VERSION 5.7 ;
  NOWIREEXTENSIONATPIN ON ;
  DIVIDERCHAR "/" ;
  BUSBITCHARS "[]" ;
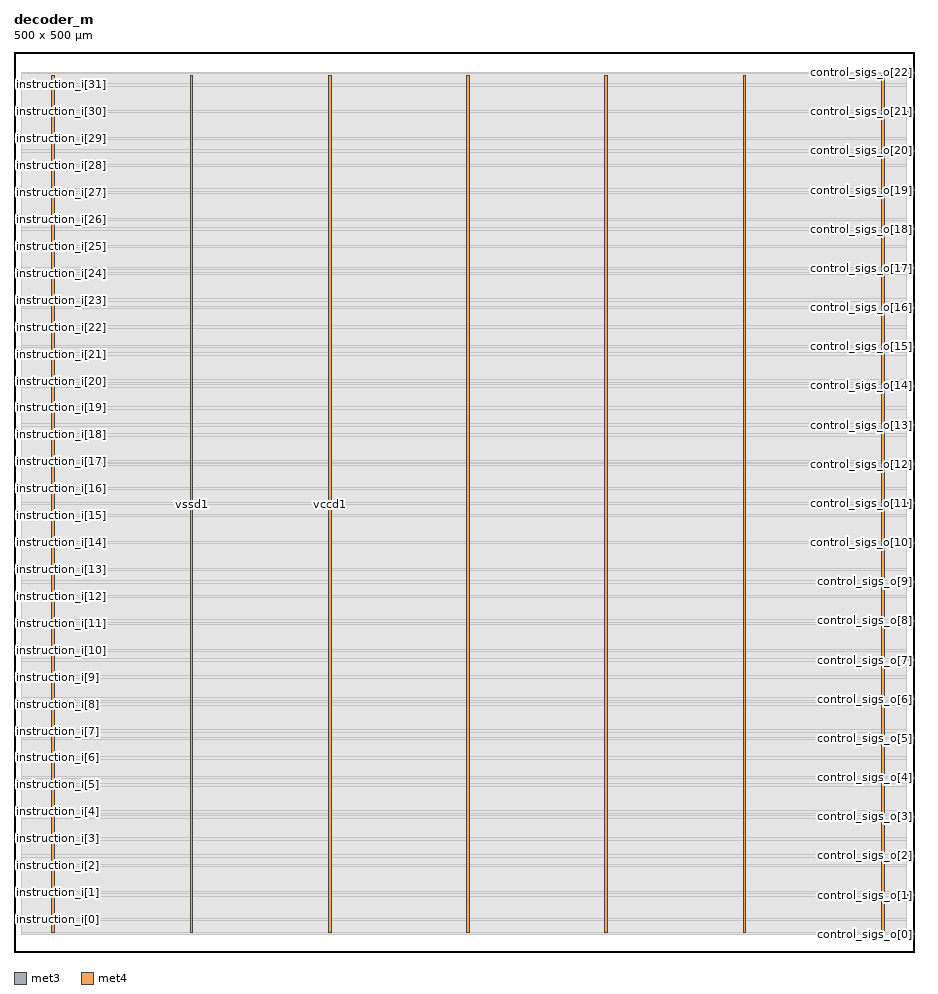
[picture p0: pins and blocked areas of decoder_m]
MACRO decoder_m
  CLASS BLOCK ;
  FOREIGN decoder_m ;
  ORIGIN 0.000 0.000 ;
  SIZE 500.000 BY 500.000 ;
  PIN control_sigs_o[0]
    DIRECTION OUTPUT TRISTATE ;
    USE SIGNAL ;
    ANTENNADIFFAREA 2.673000 ;
    PORT
      LAYER met3 ;
        RECT 496.000 9.560 500.000 10.160 ;
    END
  END control_sigs_o[0]
  PIN control_sigs_o[10]
    DIRECTION OUTPUT TRISTATE ;
    USE SIGNAL ;
    ANTENNADIFFAREA 2.673000 ;
    PORT
      LAYER met3 ;
        RECT 496.000 227.160 500.000 227.760 ;
    END
  END control_sigs_o[10]
  PIN control_sigs_o[11]
    DIRECTION OUTPUT TRISTATE ;
    USE SIGNAL ;
    ANTENNADIFFAREA 2.673000 ;
    PORT
      LAYER met3 ;
        RECT 496.000 248.920 500.000 249.520 ;
    END
  END control_sigs_o[11]
  PIN control_sigs_o[12]
    DIRECTION OUTPUT TRISTATE ;
    USE SIGNAL ;
    ANTENNADIFFAREA 2.673000 ;
    PORT
      LAYER met3 ;
        RECT 496.000 270.680 500.000 271.280 ;
    END
  END control_sigs_o[12]
  PIN control_sigs_o[13]
    DIRECTION OUTPUT TRISTATE ;
    USE SIGNAL ;
    ANTENNADIFFAREA 2.673000 ;
    PORT
      LAYER met3 ;
        RECT 496.000 292.440 500.000 293.040 ;
    END
  END control_sigs_o[13]
  PIN control_sigs_o[14]
    DIRECTION OUTPUT TRISTATE ;
    USE SIGNAL ;
    ANTENNADIFFAREA 2.673000 ;
    PORT
      LAYER met3 ;
        RECT 496.000 314.200 500.000 314.800 ;
    END
  END control_sigs_o[14]
  PIN control_sigs_o[15]
    DIRECTION OUTPUT TRISTATE ;
    USE SIGNAL ;
    ANTENNADIFFAREA 2.673000 ;
    PORT
      LAYER met3 ;
        RECT 496.000 335.960 500.000 336.560 ;
    END
  END control_sigs_o[15]
  PIN control_sigs_o[16]
    DIRECTION OUTPUT TRISTATE ;
    USE SIGNAL ;
    ANTENNADIFFAREA 2.673000 ;
    PORT
      LAYER met3 ;
        RECT 496.000 357.720 500.000 358.320 ;
    END
  END control_sigs_o[16]
  PIN control_sigs_o[17]
    DIRECTION OUTPUT TRISTATE ;
    USE SIGNAL ;
    ANTENNADIFFAREA 2.673000 ;
    PORT
      LAYER met3 ;
        RECT 496.000 379.480 500.000 380.080 ;
    END
  END control_sigs_o[17]
  PIN control_sigs_o[18]
    DIRECTION OUTPUT TRISTATE ;
    USE SIGNAL ;
    ANTENNADIFFAREA 2.673000 ;
    PORT
      LAYER met3 ;
        RECT 496.000 401.240 500.000 401.840 ;
    END
  END control_sigs_o[18]
  PIN control_sigs_o[19]
    DIRECTION OUTPUT TRISTATE ;
    USE SIGNAL ;
    ANTENNADIFFAREA 2.673000 ;
    PORT
      LAYER met3 ;
        RECT 496.000 423.000 500.000 423.600 ;
    END
  END control_sigs_o[19]
  PIN control_sigs_o[1]
    DIRECTION OUTPUT TRISTATE ;
    USE SIGNAL ;
    ANTENNADIFFAREA 2.673000 ;
    PORT
      LAYER met3 ;
        RECT 496.000 31.320 500.000 31.920 ;
    END
  END control_sigs_o[1]
  PIN control_sigs_o[20]
    DIRECTION OUTPUT TRISTATE ;
    USE SIGNAL ;
    ANTENNADIFFAREA 2.673000 ;
    PORT
      LAYER met3 ;
        RECT 496.000 444.760 500.000 445.360 ;
    END
  END control_sigs_o[20]
  PIN control_sigs_o[21]
    DIRECTION OUTPUT TRISTATE ;
    USE SIGNAL ;
    ANTENNADIFFAREA 2.673000 ;
    PORT
      LAYER met3 ;
        RECT 496.000 466.520 500.000 467.120 ;
    END
  END control_sigs_o[21]
  PIN control_sigs_o[22]
    DIRECTION OUTPUT TRISTATE ;
    USE SIGNAL ;
    ANTENNADIFFAREA 2.673000 ;
    PORT
      LAYER met3 ;
        RECT 496.000 488.280 500.000 488.880 ;
    END
  END control_sigs_o[22]
  PIN control_sigs_o[2]
    DIRECTION OUTPUT TRISTATE ;
    USE SIGNAL ;
    ANTENNADIFFAREA 2.673000 ;
    PORT
      LAYER met3 ;
        RECT 496.000 53.080 500.000 53.680 ;
    END
  END control_sigs_o[2]
  PIN control_sigs_o[3]
    DIRECTION OUTPUT TRISTATE ;
    USE SIGNAL ;
    ANTENNADIFFAREA 2.673000 ;
    PORT
      LAYER met3 ;
        RECT 496.000 74.840 500.000 75.440 ;
    END
  END control_sigs_o[3]
  PIN control_sigs_o[4]
    DIRECTION OUTPUT TRISTATE ;
    USE SIGNAL ;
    ANTENNADIFFAREA 2.673000 ;
    PORT
      LAYER met3 ;
        RECT 496.000 96.600 500.000 97.200 ;
    END
  END control_sigs_o[4]
  PIN control_sigs_o[5]
    DIRECTION OUTPUT TRISTATE ;
    USE SIGNAL ;
    ANTENNADIFFAREA 2.673000 ;
    PORT
      LAYER met3 ;
        RECT 496.000 118.360 500.000 118.960 ;
    END
  END control_sigs_o[5]
  PIN control_sigs_o[6]
    DIRECTION OUTPUT TRISTATE ;
    USE SIGNAL ;
    ANTENNADIFFAREA 2.673000 ;
    PORT
      LAYER met3 ;
        RECT 496.000 140.120 500.000 140.720 ;
    END
  END control_sigs_o[6]
  PIN control_sigs_o[7]
    DIRECTION OUTPUT TRISTATE ;
    USE SIGNAL ;
    ANTENNADIFFAREA 2.673000 ;
    PORT
      LAYER met3 ;
        RECT 496.000 161.880 500.000 162.480 ;
    END
  END control_sigs_o[7]
  PIN control_sigs_o[8]
    DIRECTION OUTPUT TRISTATE ;
    USE SIGNAL ;
    ANTENNADIFFAREA 2.673000 ;
    PORT
      LAYER met3 ;
        RECT 496.000 183.640 500.000 184.240 ;
    END
  END control_sigs_o[8]
  PIN control_sigs_o[9]
    DIRECTION OUTPUT TRISTATE ;
    USE SIGNAL ;
    ANTENNADIFFAREA 2.673000 ;
    PORT
      LAYER met3 ;
        RECT 496.000 205.400 500.000 206.000 ;
    END
  END control_sigs_o[9]
  PIN instruction_i[0]
    DIRECTION INPUT ;
    USE SIGNAL ;
    PORT
      LAYER met3 ;
        RECT 0.000 17.720 4.000 18.320 ;
    END
  END instruction_i[0]
  PIN instruction_i[10]
    DIRECTION INPUT ;
    USE SIGNAL ;
    PORT
      LAYER met3 ;
        RECT 0.000 167.320 4.000 167.920 ;
    END
  END instruction_i[10]
  PIN instruction_i[11]
    DIRECTION INPUT ;
    USE SIGNAL ;
    ANTENNAGATEAREA 0.196500 ;
    PORT
      LAYER met3 ;
        RECT 0.000 182.280 4.000 182.880 ;
    END
  END instruction_i[11]
  PIN instruction_i[12]
    DIRECTION INPUT ;
    USE SIGNAL ;
    ANTENNAGATEAREA 0.196500 ;
    PORT
      LAYER met3 ;
        RECT 0.000 197.240 4.000 197.840 ;
    END
  END instruction_i[12]
  PIN instruction_i[13]
    DIRECTION INPUT ;
    USE SIGNAL ;
    PORT
      LAYER met3 ;
        RECT 0.000 212.200 4.000 212.800 ;
    END
  END instruction_i[13]
  PIN instruction_i[14]
    DIRECTION INPUT ;
    USE SIGNAL ;
    PORT
      LAYER met3 ;
        RECT 0.000 227.160 4.000 227.760 ;
    END
  END instruction_i[14]
  PIN instruction_i[15]
    DIRECTION INPUT ;
    USE SIGNAL ;
    PORT
      LAYER met3 ;
        RECT 0.000 242.120 4.000 242.720 ;
    END
  END instruction_i[15]
  PIN instruction_i[16]
    DIRECTION INPUT ;
    USE SIGNAL ;
    PORT
      LAYER met3 ;
        RECT 0.000 257.080 4.000 257.680 ;
    END
  END instruction_i[16]
  PIN instruction_i[17]
    DIRECTION INPUT ;
    USE SIGNAL ;
    ANTENNAGATEAREA 0.196500 ;
    PORT
      LAYER met3 ;
        RECT 0.000 272.040 4.000 272.640 ;
    END
  END instruction_i[17]
  PIN instruction_i[18]
    DIRECTION INPUT ;
    USE SIGNAL ;
    ANTENNAGATEAREA 0.196500 ;
    PORT
      LAYER met3 ;
        RECT 0.000 287.000 4.000 287.600 ;
    END
  END instruction_i[18]
  PIN instruction_i[19]
    DIRECTION INPUT ;
    USE SIGNAL ;
    PORT
      LAYER met3 ;
        RECT 0.000 301.960 4.000 302.560 ;
    END
  END instruction_i[19]
  PIN instruction_i[1]
    DIRECTION INPUT ;
    USE SIGNAL ;
    PORT
      LAYER met3 ;
        RECT 0.000 32.680 4.000 33.280 ;
    END
  END instruction_i[1]
  PIN instruction_i[20]
    DIRECTION INPUT ;
    USE SIGNAL ;
    PORT
      LAYER met3 ;
        RECT 0.000 316.920 4.000 317.520 ;
    END
  END instruction_i[20]
  PIN instruction_i[21]
    DIRECTION INPUT ;
    USE SIGNAL ;
    PORT
      LAYER met3 ;
        RECT 0.000 331.880 4.000 332.480 ;
    END
  END instruction_i[21]
  PIN instruction_i[22]
    DIRECTION INPUT ;
    USE SIGNAL ;
    PORT
      LAYER met3 ;
        RECT 0.000 346.840 4.000 347.440 ;
    END
  END instruction_i[22]
  PIN instruction_i[23]
    DIRECTION INPUT ;
    USE SIGNAL ;
    ANTENNAGATEAREA 0.159000 ;
    PORT
      LAYER met3 ;
        RECT 0.000 361.800 4.000 362.400 ;
    END
  END instruction_i[23]
  PIN instruction_i[24]
    DIRECTION INPUT ;
    USE SIGNAL ;
    ANTENNAGATEAREA 0.213000 ;
    PORT
      LAYER met3 ;
        RECT 0.000 376.760 4.000 377.360 ;
    END
  END instruction_i[24]
  PIN instruction_i[25]
    DIRECTION INPUT ;
    USE SIGNAL ;
    ANTENNAGATEAREA 0.213000 ;
    PORT
      LAYER met3 ;
        RECT 0.000 391.720 4.000 392.320 ;
    END
  END instruction_i[25]
  PIN instruction_i[26]
    DIRECTION INPUT ;
    USE SIGNAL ;
    ANTENNAGATEAREA 0.426000 ;
    PORT
      LAYER met3 ;
        RECT 0.000 406.680 4.000 407.280 ;
    END
  END instruction_i[26]
  PIN instruction_i[27]
    DIRECTION INPUT ;
    USE SIGNAL ;
    ANTENNAGATEAREA 0.495000 ;
    PORT
      LAYER met3 ;
        RECT 0.000 421.640 4.000 422.240 ;
    END
  END instruction_i[27]
  PIN instruction_i[28]
    DIRECTION INPUT ;
    USE SIGNAL ;
    ANTENNAGATEAREA 0.495000 ;
    PORT
      LAYER met3 ;
        RECT 0.000 436.600 4.000 437.200 ;
    END
  END instruction_i[28]
  PIN instruction_i[29]
    DIRECTION INPUT ;
    USE SIGNAL ;
    ANTENNAGATEAREA 0.426000 ;
    PORT
      LAYER met3 ;
        RECT 0.000 451.560 4.000 452.160 ;
    END
  END instruction_i[29]
  PIN instruction_i[2]
    DIRECTION INPUT ;
    USE SIGNAL ;
    PORT
      LAYER met3 ;
        RECT 0.000 47.640 4.000 48.240 ;
    END
  END instruction_i[2]
  PIN instruction_i[30]
    DIRECTION INPUT ;
    USE SIGNAL ;
    ANTENNAGATEAREA 0.426000 ;
    PORT
      LAYER met3 ;
        RECT 0.000 466.520 4.000 467.120 ;
    END
  END instruction_i[30]
  PIN instruction_i[31]
    DIRECTION INPUT ;
    USE SIGNAL ;
    ANTENNAGATEAREA 0.426000 ;
    PORT
      LAYER met3 ;
        RECT 0.000 481.480 4.000 482.080 ;
    END
  END instruction_i[31]
  PIN instruction_i[3]
    DIRECTION INPUT ;
    USE SIGNAL ;
    PORT
      LAYER met3 ;
        RECT 0.000 62.600 4.000 63.200 ;
    END
  END instruction_i[3]
  PIN instruction_i[4]
    DIRECTION INPUT ;
    USE SIGNAL ;
    PORT
      LAYER met3 ;
        RECT 0.000 77.560 4.000 78.160 ;
    END
  END instruction_i[4]
  PIN instruction_i[5]
    DIRECTION INPUT ;
    USE SIGNAL ;
    PORT
      LAYER met3 ;
        RECT 0.000 92.520 4.000 93.120 ;
    END
  END instruction_i[5]
  PIN instruction_i[6]
    DIRECTION INPUT ;
    USE SIGNAL ;
    PORT
      LAYER met3 ;
        RECT 0.000 107.480 4.000 108.080 ;
    END
  END instruction_i[6]
  PIN instruction_i[7]
    DIRECTION INPUT ;
    USE SIGNAL ;
    PORT
      LAYER met3 ;
        RECT 0.000 122.440 4.000 123.040 ;
    END
  END instruction_i[7]
  PIN instruction_i[8]
    DIRECTION INPUT ;
    USE SIGNAL ;
    PORT
      LAYER met3 ;
        RECT 0.000 137.400 4.000 138.000 ;
    END
  END instruction_i[8]
  PIN instruction_i[9]
    DIRECTION INPUT ;
    USE SIGNAL ;
    PORT
      LAYER met3 ;
        RECT 0.000 152.360 4.000 152.960 ;
    END
  END instruction_i[9]
  PIN vccd1
    DIRECTION INOUT ;
    USE POWER ;
    PORT
      LAYER met4 ;
        RECT 21.040 10.640 22.640 487.120 ;
    END
    PORT
      LAYER met4 ;
        RECT 174.640 10.640 176.240 487.120 ;
    END
    PORT
      LAYER met4 ;
        RECT 328.240 10.640 329.840 487.120 ;
    END
    PORT
      LAYER met4 ;
        RECT 481.840 10.640 483.440 487.120 ;
    END
  END vccd1
  PIN vssd1
    DIRECTION INOUT ;
    USE GROUND ;
    PORT
      LAYER met4 ;
        RECT 97.840 10.640 99.440 487.120 ;
    END
    PORT
      LAYER met4 ;
        RECT 251.440 10.640 253.040 487.120 ;
    END
    PORT
      LAYER met4 ;
        RECT 405.040 10.640 406.640 487.120 ;
    END
  END vssd1
  OBS
      LAYER li1 ;
        RECT 5.520 10.795 494.040 486.965 ;
      LAYER met1 ;
        RECT 4.670 10.640 494.040 487.120 ;
      LAYER met2 ;
        RECT 4.690 9.675 492.560 488.765 ;
      LAYER met3 ;
        RECT 3.990 487.880 495.600 488.745 ;
        RECT 3.990 482.480 496.000 487.880 ;
        RECT 4.400 481.080 496.000 482.480 ;
        RECT 3.990 467.520 496.000 481.080 ;
        RECT 4.400 466.120 495.600 467.520 ;
        RECT 3.990 452.560 496.000 466.120 ;
        RECT 4.400 451.160 496.000 452.560 ;
        RECT 3.990 445.760 496.000 451.160 ;
        RECT 3.990 444.360 495.600 445.760 ;
        RECT 3.990 437.600 496.000 444.360 ;
        RECT 4.400 436.200 496.000 437.600 ;
        RECT 3.990 424.000 496.000 436.200 ;
        RECT 3.990 422.640 495.600 424.000 ;
        RECT 4.400 422.600 495.600 422.640 ;
        RECT 4.400 421.240 496.000 422.600 ;
        RECT 3.990 407.680 496.000 421.240 ;
        RECT 4.400 406.280 496.000 407.680 ;
        RECT 3.990 402.240 496.000 406.280 ;
        RECT 3.990 400.840 495.600 402.240 ;
        RECT 3.990 392.720 496.000 400.840 ;
        RECT 4.400 391.320 496.000 392.720 ;
        RECT 3.990 380.480 496.000 391.320 ;
        RECT 3.990 379.080 495.600 380.480 ;
        RECT 3.990 377.760 496.000 379.080 ;
        RECT 4.400 376.360 496.000 377.760 ;
        RECT 3.990 362.800 496.000 376.360 ;
        RECT 4.400 361.400 496.000 362.800 ;
        RECT 3.990 358.720 496.000 361.400 ;
        RECT 3.990 357.320 495.600 358.720 ;
        RECT 3.990 347.840 496.000 357.320 ;
        RECT 4.400 346.440 496.000 347.840 ;
        RECT 3.990 336.960 496.000 346.440 ;
        RECT 3.990 335.560 495.600 336.960 ;
        RECT 3.990 332.880 496.000 335.560 ;
        RECT 4.400 331.480 496.000 332.880 ;
        RECT 3.990 317.920 496.000 331.480 ;
        RECT 4.400 316.520 496.000 317.920 ;
        RECT 3.990 315.200 496.000 316.520 ;
        RECT 3.990 313.800 495.600 315.200 ;
        RECT 3.990 302.960 496.000 313.800 ;
        RECT 4.400 301.560 496.000 302.960 ;
        RECT 3.990 293.440 496.000 301.560 ;
        RECT 3.990 292.040 495.600 293.440 ;
        RECT 3.990 288.000 496.000 292.040 ;
        RECT 4.400 286.600 496.000 288.000 ;
        RECT 3.990 273.040 496.000 286.600 ;
        RECT 4.400 271.680 496.000 273.040 ;
        RECT 4.400 271.640 495.600 271.680 ;
        RECT 3.990 270.280 495.600 271.640 ;
        RECT 3.990 258.080 496.000 270.280 ;
        RECT 4.400 256.680 496.000 258.080 ;
        RECT 3.990 249.920 496.000 256.680 ;
        RECT 3.990 248.520 495.600 249.920 ;
        RECT 3.990 243.120 496.000 248.520 ;
        RECT 4.400 241.720 496.000 243.120 ;
        RECT 3.990 228.160 496.000 241.720 ;
        RECT 4.400 226.760 495.600 228.160 ;
        RECT 3.990 213.200 496.000 226.760 ;
        RECT 4.400 211.800 496.000 213.200 ;
        RECT 3.990 206.400 496.000 211.800 ;
        RECT 3.990 205.000 495.600 206.400 ;
        RECT 3.990 198.240 496.000 205.000 ;
        RECT 4.400 196.840 496.000 198.240 ;
        RECT 3.990 184.640 496.000 196.840 ;
        RECT 3.990 183.280 495.600 184.640 ;
        RECT 4.400 183.240 495.600 183.280 ;
        RECT 4.400 181.880 496.000 183.240 ;
        RECT 3.990 168.320 496.000 181.880 ;
        RECT 4.400 166.920 496.000 168.320 ;
        RECT 3.990 162.880 496.000 166.920 ;
        RECT 3.990 161.480 495.600 162.880 ;
        RECT 3.990 153.360 496.000 161.480 ;
        RECT 4.400 151.960 496.000 153.360 ;
        RECT 3.990 141.120 496.000 151.960 ;
        RECT 3.990 139.720 495.600 141.120 ;
        RECT 3.990 138.400 496.000 139.720 ;
        RECT 4.400 137.000 496.000 138.400 ;
        RECT 3.990 123.440 496.000 137.000 ;
        RECT 4.400 122.040 496.000 123.440 ;
        RECT 3.990 119.360 496.000 122.040 ;
        RECT 3.990 117.960 495.600 119.360 ;
        RECT 3.990 108.480 496.000 117.960 ;
        RECT 4.400 107.080 496.000 108.480 ;
        RECT 3.990 97.600 496.000 107.080 ;
        RECT 3.990 96.200 495.600 97.600 ;
        RECT 3.990 93.520 496.000 96.200 ;
        RECT 4.400 92.120 496.000 93.520 ;
        RECT 3.990 78.560 496.000 92.120 ;
        RECT 4.400 77.160 496.000 78.560 ;
        RECT 3.990 75.840 496.000 77.160 ;
        RECT 3.990 74.440 495.600 75.840 ;
        RECT 3.990 63.600 496.000 74.440 ;
        RECT 4.400 62.200 496.000 63.600 ;
        RECT 3.990 54.080 496.000 62.200 ;
        RECT 3.990 52.680 495.600 54.080 ;
        RECT 3.990 48.640 496.000 52.680 ;
        RECT 4.400 47.240 496.000 48.640 ;
        RECT 3.990 33.680 496.000 47.240 ;
        RECT 4.400 32.320 496.000 33.680 ;
        RECT 4.400 32.280 495.600 32.320 ;
        RECT 3.990 30.920 495.600 32.280 ;
        RECT 3.990 18.720 496.000 30.920 ;
        RECT 4.400 17.320 496.000 18.720 ;
        RECT 3.990 10.560 496.000 17.320 ;
        RECT 3.990 9.695 495.600 10.560 ;
  END
END decoder_m
END LIBRARY

